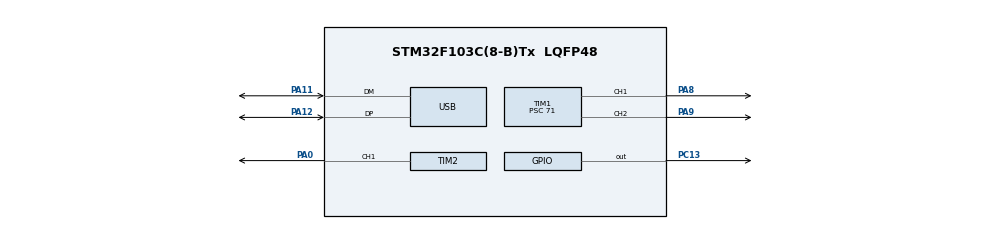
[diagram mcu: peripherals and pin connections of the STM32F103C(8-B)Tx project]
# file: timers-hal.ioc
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Mcu.Family=STM32F1
Mcu.Name=STM32F103C(8-B)Tx
Mcu.Package=LQFP48
NVIC.PriorityGroup=NVIC_PRIORITYGROUP_4
NVIC.USB_LP_CAN1_RX0_IRQn=true\:0\:0\:false\:false\:true\:false\:true
PA0-WKUP.Signal=S_TIM2_CH1_ETR
PA11.Mode=Device
PA11.Signal=USB_DM
PA12.Mode=Device
PA12.Signal=USB_DP
PA13.Mode=Serial_Wire
PA13.Signal=SYS_JTMS-SWDIO
PA14.Mode=Serial_Wire
PA14.Signal=SYS_JTCK-SWCLK
PA8.Signal=S_TIM1_CH1
PA9.Signal=S_TIM1_CH2
PC13-TAMPER-RTC.GPIO_ModeDefaultOutputPP=GPIO_MODE_OUTPUT_PP
PC13-TAMPER-RTC.GPIO_PuPd=GPIO_NOPULL
PC13-TAMPER-RTC.PinState=GPIO_PIN_SET
PC13-TAMPER-RTC.Signal=GPIO_Output
PC14-OSC32_IN.Mode=LSE-External-Oscillator
PC14-OSC32_IN.Signal=RCC_OSC32_IN
PC15-OSC32_OUT.Mode=LSE-External-Oscillator
PC15-OSC32_OUT.Signal=RCC_OSC32_OUT
PD0-OSC_IN.Mode=HSE-External-Oscillator
PD0-OSC_IN.Signal=RCC_OSC_IN
PD1-OSC_OUT.Mode=HSE-External-Oscillator
PD1-OSC_OUT.Signal=RCC_OSC_OUT
ProjectManager.HeapSize=0x200
ProjectManager.StackSize=0x400
ProjectManager.TargetToolchain=STM32CubeIDE
RCC.AHBFreq_Value=72000000
RCC.APB1CLKDivider=RCC_HCLK_DIV2
RCC.APB1Freq_Value=36000000
RCC.APB1TimFreq_Value=72000000
RCC.APB2Freq_Value=72000000
RCC.APB2TimFreq_Value=72000000
RCC.HCLKFreq_Value=72000000
RCC.PLLMUL=RCC_PLL_MUL9
RCC.PLLSourceVirtual=RCC_PLLSOURCE_HSE
RCC.SYSCLKFreq_VALUE=72000000
RCC.SYSCLKSource=RCC_SYSCLKSOURCE_PLLCLK
RCC.USBFreq_Value=48000000
RCC.USBPrescaler=RCC_USBCLKSOURCE_PLL_DIV1_5
SH.S_TIM1_CH1.0=TIM1_CH1,PWM Generation1 CH1
SH.S_TIM1_CH2.0=TIM1_CH2,PWM Generation2 CH2
SH.S_TIM2_CH1_ETR.0=TIM2_CH1,PWM Generation1 CH1
TIM1.Channel-PWM\ Generation1\ CH1=TIM_CHANNEL_1
TIM1.Channel-PWM\ Generation2\ CH2=TIM_CHANNEL_2
TIM1.OCMode_PWM-PWM\ Generation2\ CH2=TIM_OCMODE_PWM2
TIM1.Period=1000
TIM1.Prescaler=71
TIM1.Pulse-PWM\ Generation1\ CH1=300
TIM1.Pulse-PWM\ Generation2\ CH2=300
TIM2.Channel-PWM\ Generation1\ CH1=TIM_CHANNEL_1
TIM2.Period=1000
TIM2.Prescaler=720-1
TIM2.Pulse-PWM\ Generation1\ CH1=500
USB_DEVICE.CLASS_NAME_FS=CDC
USB_DEVICE.VirtualMode=Cdc
USB_DEVICE.VirtualModeFS=Cdc_FS
VP_TIM1_VS_ClockSourceINT.Mode=Internal
VP_TIM2_VS_ClockSourceINT.Mode=Internal
VP_USB_DEVICE_VS_USB_DEVICE_CDC_FS.Mode=CDC_FS
board=custom

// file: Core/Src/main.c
/* USER CODE BEGIN Header */
/**
  ******************************************************************************
  * @file           : main.c
  * @brief          : Main program body
  ******************************************************************************
  * @attention
  *
  * <h2><center>&copy; Copyright (c) 2021 STMicroelectronics.
  * All rights reserved.</center></h2>
  *
  * This software component is licensed by ST under Ultimate Liberty license
  * SLA0044, the "License"; You may not use this file except in compliance with
  * the License. You may obtain a copy of the License at:
  *                             www.st.com/SLA0044
  *
  ******************************************************************************
  */
/* USER CODE END Header */
#include "main.h"
#include "usb_device.h"

TIM_HandleTypeDef htim1;
TIM_HandleTypeDef htim2;

void SystemClock_Config(void);
static void MX_GPIO_Init(void);
static void MX_TIM1_Init(void);
static void MX_TIM2_Init(void);

int main(void)
{

  /* MCU Configuration--------------------------------------------------------*/

  /* Reset of all peripherals, Initializes the Flash interface and the Systick. */
  HAL_Init();

  /* Configure the system clock */
  SystemClock_Config();

  /* Initialize all configured peripherals */
  MX_GPIO_Init();
  MX_USB_DEVICE_Init();
  MX_TIM1_Init();
  MX_TIM2_Init();

  /* Infinite loop */
  /* USER CODE BEGIN WHILE */
  HAL_TIM_Base_Start(&htim1);
  HAL_TIM_Base_Start(&htim2);
  HAL_TIM_PWM_Start(&htim1, TIM_CHANNEL_1);
  HAL_TIM_PWM_Start(&htim1, TIM_CHANNEL_2);
  while (1)
  {
    /* USER CODE END WHILE */

    /* USER CODE BEGIN 3 */
    for (uint32_t i=0; i < 1000; i+=10){
      __HAL_TIM_SET_COMPARE(&htim1, TIM_CHANNEL_1, i); // increase PWM
      __HAL_TIM_SET_COMPARE(&htim1, TIM_CHANNEL_2, 1000-i); // decrease PWM
      HAL_Delay(10);
    }
    for (uint32_t i=0; i < 1000; i+=10){
      __HAL_TIM_SET_COMPARE(&htim1, TIM_CHANNEL_1, 1000-i); // decrease PWM
      __HAL_TIM_SET_COMPARE(&htim1, TIM_CHANNEL_2, i); // increase PWM
      HAL_Delay(10);
    }
  }
  /* USER CODE END 3 */
}

void SystemClock_Config(void)
{
  RCC_OscInitTypeDef RCC_OscInitStruct = {0};
  RCC_ClkInitTypeDef RCC_ClkInitStruct = {0};
  RCC_PeriphCLKInitTypeDef PeriphClkInit = {0};

  /** Initializes the RCC Oscillators according to the specified parameters
  * in the RCC_OscInitTypeDef structure.
  */
  RCC_OscInitStruct.OscillatorType = RCC_OSCILLATORTYPE_HSE;
  RCC_OscInitStruct.HSEState = RCC_HSE_ON;
  RCC_OscInitStruct.HSEPredivValue = RCC_HSE_PREDIV_DIV1;
  RCC_OscInitStruct.HSIState = RCC_HSI_ON;
  RCC_OscInitStruct.PLL.PLLState = RCC_PLL_ON;
  RCC_OscInitStruct.PLL.PLLSource = RCC_PLLSOURCE_HSE;
  RCC_OscInitStruct.PLL.PLLMUL = RCC_PLL_MUL9;
  if (HAL_RCC_OscConfig(&RCC_OscInitStruct) != HAL_OK)
  {
    Error_Handler();
  }
  /** Initializes the CPU, AHB and APB buses clocks
  */
  RCC_ClkInitStruct.ClockType = RCC_CLOCKTYPE_HCLK|RCC_CLOCKTYPE_SYSCLK
                              |RCC_CLOCKTYPE_PCLK1|RCC_CLOCKTYPE_PCLK2;
  RCC_ClkInitStruct.SYSCLKSource = RCC_SYSCLKSOURCE_PLLCLK;
  RCC_ClkInitStruct.AHBCLKDivider = RCC_SYSCLK_DIV4;
  RCC_ClkInitStruct.APB1CLKDivider = RCC_HCLK_DIV1;
  RCC_ClkInitStruct.APB2CLKDivider = RCC_HCLK_DIV1;

  if (HAL_RCC_ClockConfig(&RCC_ClkInitStruct, FLASH_LATENCY_2) != HAL_OK)
  {
    Error_Handler();
  }
  PeriphClkInit.PeriphClockSelection = RCC_PERIPHCLK_USB;
  PeriphClkInit.UsbClockSelection = RCC_USBCLKSOURCE_PLL_DIV1_5;
  if (HAL_RCCEx_PeriphCLKConfig(&PeriphClkInit) != HAL_OK)
  {
    Error_Handler();
  }
}

static void MX_TIM1_Init(void)
{

  TIM_ClockConfigTypeDef sClockSourceConfig = {0};
  TIM_MasterConfigTypeDef sMasterConfig = {0};
  TIM_OC_InitTypeDef sConfigOC = {0};
  TIM_BreakDeadTimeConfigTypeDef sBreakDeadTimeConfig = {0};

  htim1.Instance = TIM1;
  htim1.Init.Prescaler = 18-1;
  htim1.Init.CounterMode = TIM_COUNTERMODE_UP;
  htim1.Init.Period = 1000;
  htim1.Init.ClockDivision = TIM_CLOCKDIVISION_DIV1;
  htim1.Init.RepetitionCounter = 0;
  htim1.Init.AutoReloadPreload = TIM_AUTORELOAD_PRELOAD_DISABLE;
  if (HAL_TIM_Base_Init(&htim1) != HAL_OK)
  {
    Error_Handler();
  }
  sClockSourceConfig.ClockSource = TIM_CLOCKSOURCE_INTERNAL;
  if (HAL_TIM_ConfigClockSource(&htim1, &sClockSourceConfig) != HAL_OK)
  {
    Error_Handler();
  }
  if (HAL_TIM_PWM_Init(&htim1) != HAL_OK)
  {
    Error_Handler();
  }
  sMasterConfig.MasterOutputTrigger = TIM_TRGO_RESET;
  sMasterConfig.MasterSlaveMode = TIM_MASTERSLAVEMODE_DISABLE;
  if (HAL_TIMEx_MasterConfigSynchronization(&htim1, &sMasterConfig) != HAL_OK)
  {
    Error_Handler();
  }
  sConfigOC.OCMode = TIM_OCMODE_PWM1;
  sConfigOC.Pulse = 300;
  sConfigOC.OCPolarity = TIM_OCPOLARITY_HIGH;
  sConfigOC.OCNPolarity = TIM_OCNPOLARITY_HIGH;
  sConfigOC.OCFastMode = TIM_OCFAST_DISABLE;
  sConfigOC.OCIdleState = TIM_OCIDLESTATE_RESET;
  sConfigOC.OCNIdleState = TIM_OCNIDLESTATE_RESET;
  if (HAL_TIM_PWM_ConfigChannel(&htim1, &sConfigOC, TIM_CHANNEL_1) != HAL_OK)
  {
    Error_Handler();
  }
  sConfigOC.Pulse = 700;
  if (HAL_TIM_PWM_ConfigChannel(&htim1, &sConfigOC, TIM_CHANNEL_2) != HAL_OK)
  {
    Error_Handler();
  }
  sBreakDeadTimeConfig.OffStateRunMode = TIM_OSSR_DISABLE;
  sBreakDeadTimeConfig.OffStateIDLEMode = TIM_OSSI_DISABLE;
  sBreakDeadTimeConfig.LockLevel = TIM_LOCKLEVEL_OFF;
  sBreakDeadTimeConfig.DeadTime = 0;
  sBreakDeadTimeConfig.BreakState = TIM_BREAK_DISABLE;
  sBreakDeadTimeConfig.BreakPolarity = TIM_BREAKPOLARITY_HIGH;
  sBreakDeadTimeConfig.AutomaticOutput = TIM_AUTOMATICOUTPUT_DISABLE;
  if (HAL_TIMEx_ConfigBreakDeadTime(&htim1, &sBreakDeadTimeConfig) != HAL_OK)
  {
    Error_Handler();
  }
  HAL_TIM_MspPostInit(&htim1);

}

static void MX_TIM2_Init(void)
{

  TIM_ClockConfigTypeDef sClockSourceConfig = {0};
  TIM_MasterConfigTypeDef sMasterConfig = {0};
  TIM_OC_InitTypeDef sConfigOC = {0};

  htim2.Instance = TIM2;
  htim2.Init.Prescaler = 720-1;
  htim2.Init.CounterMode = TIM_COUNTERMODE_UP;
  htim2.Init.Period = 1000;
  htim2.Init.ClockDivision = TIM_CLOCKDIVISION_DIV1;
  htim2.Init.AutoReloadPreload = TIM_AUTORELOAD_PRELOAD_DISABLE;
  if (HAL_TIM_Base_Init(&htim2) != HAL_OK)
  {
    Error_Handler();
  }
  sClockSourceConfig.ClockSource = TIM_CLOCKSOURCE_INTERNAL;
  if (HAL_TIM_ConfigClockSource(&htim2, &sClockSourceConfig) != HAL_OK)
  {
    Error_Handler();
  }
  if (HAL_TIM_PWM_Init(&htim2) != HAL_OK)
  {
    Error_Handler();
  }
  sMasterConfig.MasterOutputTrigger = TIM_TRGO_RESET;
  sMasterConfig.MasterSlaveMode = TIM_MASTERSLAVEMODE_DISABLE;
  if (HAL_TIMEx_MasterConfigSynchronization(&htim2, &sMasterConfig) != HAL_OK)
  {
    Error_Handler();
  }
  sConfigOC.OCMode = TIM_OCMODE_PWM1;
  sConfigOC.Pulse = 500;
  sConfigOC.OCPolarity = TIM_OCPOLARITY_HIGH;
  sConfigOC.OCFastMode = TIM_OCFAST_DISABLE;
  if (HAL_TIM_PWM_ConfigChannel(&htim2, &sConfigOC, TIM_CHANNEL_1) != HAL_OK)
  {
    Error_Handler();
  }
  HAL_TIM_MspPostInit(&htim2);

}

static void MX_GPIO_Init(void)
{
  GPIO_InitTypeDef GPIO_InitStruct = {0};

  /* GPIO Ports Clock Enable */
  __HAL_RCC_GPIOC_CLK_ENABLE();
  __HAL_RCC_GPIOD_CLK_ENABLE();
  __HAL_RCC_GPIOA_CLK_ENABLE();

  /*Configure GPIO pin Output Level */
  HAL_GPIO_WritePin(GPIOC, GPIO_PIN_13, GPIO_PIN_SET);

  /*Configure GPIO pin : PC13 */
  GPIO_InitStruct.Pin = GPIO_PIN_13;
  GPIO_InitStruct.Mode = GPIO_MODE_OUTPUT_PP;
  GPIO_InitStruct.Pull = GPIO_NOPULL;
  GPIO_InitStruct.Speed = GPIO_SPEED_FREQ_LOW;
  HAL_GPIO_Init(GPIOC, &GPIO_InitStruct);

}

void Error_Handler(void)
{
}

/************************ (C) COPYRIGHT STMicroelectronics *****END OF FILE****/
